One B-rep face of a CAD part: STEP entity #665.
In plain terms, the planar face has unit normal (-1, 0, 0).
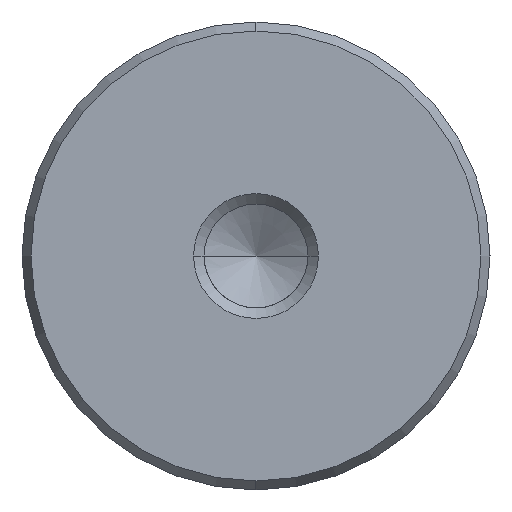
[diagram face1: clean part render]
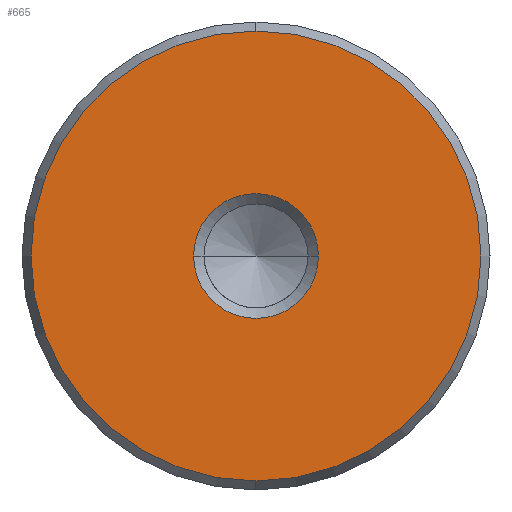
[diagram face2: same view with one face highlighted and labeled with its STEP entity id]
Its self-contained STEP definition (entity closure, numbers rounded to 3 decimals):
#579=CARTESIAN_POINT('Vertex',(0.,0.,-14.423)) ;
#582=CARTESIAN_POINT('Axis2P3D Location',(0.,0.,0.)) ;
#586=CARTESIAN_POINT('Vertex',(0.,14.423,0.)) ;
#589=CARTESIAN_POINT('Axis2P3D Location',(0.,0.,0.)) ;
#593=CARTESIAN_POINT('Vertex',(0.,0.,14.423)) ;
#615=CARTESIAN_POINT('Axis2P3D Location',(0.,0.,0.)) ;
#619=CARTESIAN_POINT('Vertex',(0.,-14.423,0.)) ;
#622=CARTESIAN_POINT('Axis2P3D Location',(0.,0.,0.)) ;
#636=CARTESIAN_POINT('Axis2P3D Location',(0.,0.,0.)) ;
#647=CARTESIAN_POINT('Axis2P3D Location',(0.,0.,0.)) ;
#651=CARTESIAN_POINT('Vertex',(0.,4.,0.)) ;
#653=CARTESIAN_POINT('Vertex',(0.,-4.,0.)) ;
#656=CARTESIAN_POINT('Axis2P3D Location',(0.,0.,0.)) ;
#583=DIRECTION('Axis2P3D Direction',(1.,0.,-0.)) ;
#590=DIRECTION('Axis2P3D Direction',(1.,0.,-0.)) ;
#616=DIRECTION('Axis2P3D Direction',(1.,0.,-0.)) ;
#623=DIRECTION('Axis2P3D Direction',(1.,0.,-0.)) ;
#637=DIRECTION('Axis2P3D Direction',(1.,0.,-0.)) ;
#638=DIRECTION('Axis2P3D XDirection',(-0.,0.,-1.)) ;
#648=DIRECTION('Axis2P3D Direction',(1.,0.,-0.)) ;
#657=DIRECTION('Axis2P3D Direction',(1.,0.,-0.)) ;
#584=AXIS2_PLACEMENT_3D('Circle Axis2P3D',#582,#583,$) ;
#591=AXIS2_PLACEMENT_3D('Circle Axis2P3D',#589,#590,$) ;
#617=AXIS2_PLACEMENT_3D('Circle Axis2P3D',#615,#616,$) ;
#624=AXIS2_PLACEMENT_3D('Circle Axis2P3D',#622,#623,$) ;
#639=AXIS2_PLACEMENT_3D('Plane Axis2P3D',#636,#637,#638) ;
#649=AXIS2_PLACEMENT_3D('Circle Axis2P3D',#647,#648,$) ;
#658=AXIS2_PLACEMENT_3D('Circle Axis2P3D',#656,#657,$) ;
#642=ORIENTED_EDGE('',*,*,#588,.F.) ;
#643=ORIENTED_EDGE('',*,*,#626,.F.) ;
#644=ORIENTED_EDGE('',*,*,#621,.F.) ;
#645=ORIENTED_EDGE('',*,*,#595,.F.) ;
#662=ORIENTED_EDGE('',*,*,#655,.T.) ;
#663=ORIENTED_EDGE('',*,*,#660,.T.) ;
#664=FACE_BOUND('',#661,.T.) ;
#665=ADVANCED_FACE('720-30x315',(#646,#664),#640,.F.) ;
#585=CIRCLE('generated circle',#584,14.423) ;
#592=CIRCLE('generated circle',#591,14.423) ;
#618=CIRCLE('generated circle',#617,14.423) ;
#625=CIRCLE('generated circle',#624,14.423) ;
#650=CIRCLE('generated circle',#649,4.) ;
#659=CIRCLE('generated circle',#658,4.) ;
#588=EDGE_CURVE('',#580,#587,#585,.T.) ;
#595=EDGE_CURVE('',#587,#594,#592,.T.) ;
#621=EDGE_CURVE('',#594,#620,#618,.T.) ;
#626=EDGE_CURVE('',#620,#580,#625,.T.) ;
#655=EDGE_CURVE('',#652,#654,#650,.T.) ;
#660=EDGE_CURVE('',#654,#652,#659,.T.) ;
#641=EDGE_LOOP('',(#642,#643,#644,#645)) ;
#661=EDGE_LOOP('',(#662,#663)) ;
#646=FACE_OUTER_BOUND('',#641,.T.) ;
#640=PLANE('Plane',#639) ;
#580=VERTEX_POINT('',#579) ;
#587=VERTEX_POINT('',#586) ;
#594=VERTEX_POINT('',#593) ;
#620=VERTEX_POINT('',#619) ;
#652=VERTEX_POINT('',#651) ;
#654=VERTEX_POINT('',#653) ;
